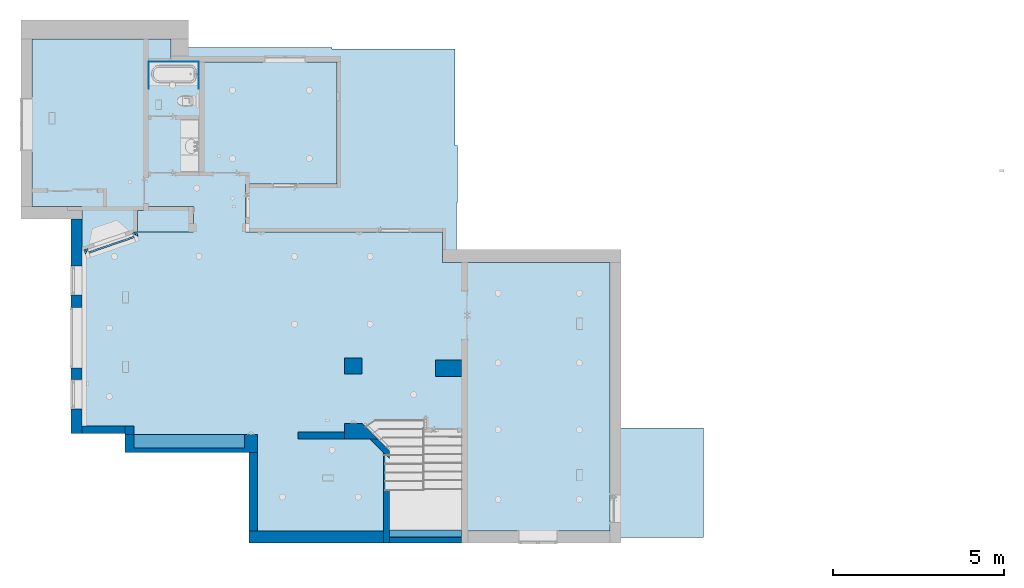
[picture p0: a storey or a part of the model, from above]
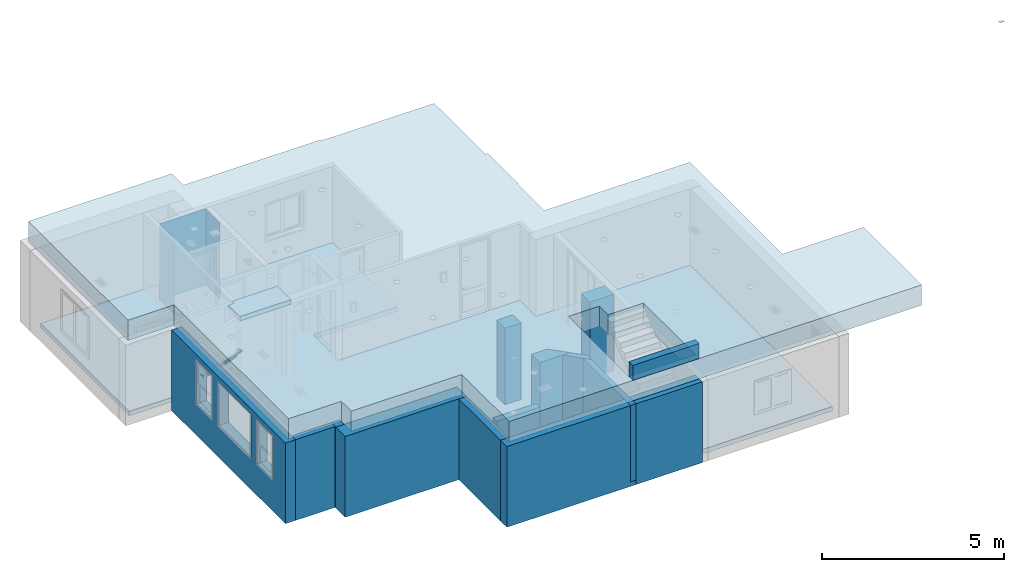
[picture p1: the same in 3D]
Properties of the parts of a building model (IFC2X3)

# File
Description: ViewDefinition [CoordinationView_V2.0, SurfaceGeometryAddOnView], Option [Elements to export: Entire project], Option [Partial Structure Display: Entire Model], Option [IFC Domain: Custom], Option [Structural Function: All Elements], Option [Convert Grid elements: On], Option [Convert IFC Annotations and ARCHICAD 2D elements: Off], Option [Convert 2D symbols of Doors and Windows: On], Option [Export geometries that Participates in Collision Detection only: On], Option [Split complex elements: Off], Option [Material Preservation: Explode where necessary], Option [IFC Model position: Survey Point and Project Origin], Option [Curtain Wall export mode: Single Element], Option [Railing export mode: Single Element], Option [Stair export mode: Single Element], Option [Properties To Export: All properties], Option [Space containment: Off], Option [Bounding Box: Off], Option [Geometry to type objects: Off], Option [Element Properties: Off], Option [Building Material Properties: Off], Option [Element Parameters: Off], Option [Component Parameters: Off], Option [IFC Base Quantities: Off], Option [Door Window Parameters: On], Option [IFC Space boundaries: Off], Option [ARCHICAD Zone Categories as IFC Space classification data: Off], Option [Element Classifications: Off]
File name: D:\PTASHKA\Canvas\Очистка\Backcountry USA\Backcountry INT.ifc
Time: 2024-10-02T13:26:50
Author: Architect
Organization: Contact Company
Written by: The EXPRESS Data Manager Version 5.02.0100.09 : 26 Sep 2013
Made in: IFC file generated by GRAPHISOFT ARCHICAD 25.0.0 INT FULL Windows version (IFC add-on version: 4013 INT FULL).
Authorization: The authorising person

# IfcSite, Site
RefLatitude: 42, 25, 2, 912200; RefLongitude: -71, -15, -30, -990400; RefElevation: 2568 in

# IfcBuildingStorey (2)
In: Building
Name | Elevation (in)
First Floor | 0
Second Floor | 127.953

# IfcSpace: Zone Names (25)
InteriorOrExteriorSpace: INTERNAL
Pset_SpaceCommon - Category: Zone Names
AC_Pset_RenovationAndPhasing - Renovation Status: Existing
Name | In | LongName
2 x 001 | First Floor | Bedroom
001 | First Floor | Storage
2 x 001 | First Floor | Bathroom
001 | First Floor | Hallway
2 x 001 | First Floor | Living room
001 | Second Floor | Kitchen
3 x 001 | Second Floor | Storage
4 x 001 | Second Floor | Hallway
2 x 001 | Second Floor | Living room
001 | Second Floor | Office
2 x 001 | Second Floor | Toilet room
001 | Second Floor | Dining room
001 | Second Floor | Bedroom
001 | Second Floor | Laundry room
001 | Second Floor | Bathroom

# IfcBeam: Plaster Cornice/Coving 125 x 205, BMR - 003
In: First Floor
Material: Generic - Structural
AC_Pset_RenovationAndPhasing - Renovation Status: New
Pset_BeamCommon - Reference: Plaster Cornice/Coving 125 x 205

# IfcBeam: Plaster Cornice/Coving 127 x 203 (2)
In: First Floor
Material: Generic - Structural
AC_Pset_RenovationAndPhasing - Renovation Status: New
Pset_BeamCommon - Reference: Plaster Cornice/Coving 127 x 203

# IfcBeam: Plaster Cornice/Coving 150 x 205 (6)
In: Second Floor
Material: Generic - Structural
AC_Pset_RenovationAndPhasing - Renovation Status: New
Pset_BeamCommon - Reference: Plaster Cornice/Coving 150 x 205

# IfcBeam: Plaster Cornice/Coving 65 x 65, BMR - 041
In: Second Floor
Material: Generic - Structural
AC_Pset_RenovationAndPhasing - Renovation Status: New
Pset_BeamCommon - Reference: Plaster Cornice/Coving 65 x 65

# IfcBeam: Tile - Wall 15 x 1120 (6)
In: Second Floor
Material: Tile - Wall
AC_Pset_RenovationAndPhasing - Renovation Status: New
Pset_BeamCommon - Reference: Tile - Wall 15 x 1120

# IfcBeam: Tile - Wall 15 x 205 (2)
In: Second Floor
Material: Tile - Wall
AC_Pset_RenovationAndPhasing - Renovation Status: New
Pset_BeamCommon - Reference: Tile - Wall 15 x 205
Name
BMR - 112
BMR - 113

# IfcBeam: Tile - Wall 15 x 2465 (4)
In: Second Floor
Material: Tile - Wall
AC_Pset_RenovationAndPhasing - Renovation Status: New
Pset_BeamCommon - Reference: Tile - Wall 15 x 2465

# IfcBeam: Tile - Wall 15 x 585 (3)
In: Second Floor
Material: Tile - Wall
AC_Pset_RenovationAndPhasing - Renovation Status: New
Pset_BeamCommon - Reference: Tile - Wall 15 x 585
Name
BMR - 113
BMR - 115
BMR - 114

# IfcBeam: Tile - Wall 5 x 125 (2)
In: Second Floor
Material: Tile - Wall
AC_Pset_RenovationAndPhasing - Renovation Status: New
Pset_BeamCommon - Reference: Tile - Wall 5 x 125

# IfcBeam: Tile - Wall 5 x 2555 (3)
In: First Floor
Material: Tile - Wall
AC_Pset_RenovationAndPhasing - Renovation Status: New
Pset_BeamCommon - Reference: Tile - Wall 5 x 2555
Name
BMR - 005
BMR - 007
BMR - 006

# IfcBeam: Tile - Wall 5 x 380 (6)
In: Second Floor
Material: Tile - Wall
AC_Pset_RenovationAndPhasing - Renovation Status: New
Pset_BeamCommon - Reference: Tile - Wall 5 x 380

# IfcBeam: Tile - Wall 6 x 76 (5)
In: Second Floor
Material: Tile - Wall
AC_Pset_RenovationAndPhasing - Renovation Status: New
Pset_BeamCommon - Reference: Tile - Wall 6 x 76

# IfcBeam: stairs floor 460 x 685, BMR - 060
In: Second Floor
Material: Generic - Structural
AC_Pset_RenovationAndPhasing - Renovation Status: New
Pset_BeamCommon - Reference: stairs floor 460 x 685

# IfcBuildingElementPart (104)
Name | In | Material
7 x Wood - Structural | First Floor | Wood - Structural
32 x Timber - Floor | First Floor | Timber - Floor
Wood - Trim | First Floor | Wood - Trim
3 x Steel - Structural | First Floor | Steel - Structural
20 x Wood - Structural | Second Floor | Wood - Structural
3 x Wood - Trim | Second Floor | Wood - Trim
38 x Steel - Structural | Second Floor | Steel - Structural

# IfcBuildingElementProxy: Base Cabinet Block 25 (28)
AC_Pset_RenovationAndPhasing - Renovation Status: New
Name | In
3 x FU - 030 | First Floor
3 x FU - 025 | Second Floor
6 x FU - 004 | Second Floor
10 x OBJ-16 | Second Floor
OBJ-15 | Second Floor
2 x FU - 026 | Second Floor
3 x FU - 007 | Second Floor

# IfcBuildingElementProxy: Base Cabinet Corner L 25, FU - 025
In: Second Floor
AC_Pset_RenovationAndPhasing - Renovation Status: New

# IfcBuildingElementProxy: Basin 25, FU - 012
In: Second Floor
AC_Pset_RenovationAndPhasing - Renovation Status: New

# IfcBuildingElementProxy: Bathtub 25, FU - 004
In: First Floor
AC_Pset_RenovationAndPhasing - Renovation Status: New

# IfcBuildingElementProxy: Bathtub Corner 25, FU - 024
In: Second Floor
AC_Pset_RenovationAndPhasing - Renovation Status: New

# IfcBuildingElementProxy: Ceiling Grille 25 (7)
In: First Floor
AC_Pset_RenovationAndPhasing - Renovation Status: New
Name
5 x FU - 013
2 x FU - 009

# IfcBuildingElementProxy: Fireplace-Traditional 25 (3)
AC_Pset_RenovationAndPhasing - Renovation Status: New
Name | In
FU - 003 | First Floor
2 x FU - 003 | Second Floor

# IfcBuildingElementProxy: GENERIC - PREFABRICATED (2)
In: Second Floor
Material: GENERIC - PREFABRICATED
AC_Pset_RenovationAndPhasing - Renovation Status: New

# IfcBuildingElementProxy: Generic - Exterior (4)
In: First Floor
Material: Generic - Exterior
AC_Pset_RenovationAndPhasing - Renovation Status: New

# IfcBuildingElementProxy: Generic - Structural (28)
Material: Generic - Structural
Name | In | Renovation Status
4 x MORPH-014 | First Floor | New
MO-22 | First Floor | New
2 x MO-01 | First Floor | New
3 x MO-11 | First Floor | New
MO-02 | First Floor | New
MORPH-013 | First Floor | New
MO-09 | First Floor | New
MORPH-016 | Second Floor | New
MORPH-013 | Second Floor | New
2 x MORPH-014 | Second Floor | New
MORPH-015 | Second Floor | New
MORPH-018 | Second Floor | New
MORPH-021 | Second Floor | New
2 x MO-11 | Second Floor | Existing
MO-12 | Second Floor | New
MO-06 | Second Floor | New
MORPH-017 | Second Floor | New
MO-05 | Second Floor | New
MORPH-001 | Second Floor | New
MO-14 | Second Floor | New

# IfcBuildingElementProxy: Glass (3)
In: Second Floor
Material: Glass
AC_Pset_RenovationAndPhasing - Renovation Status: New

# IfcBuildingElementProxy: Hood 25, FU - 017
In: Second Floor
AC_Pset_RenovationAndPhasing - Renovation Status: New

# IfcBuildingElementProxy: MISSING (2)
In: Second Floor
AC_Pset_RenovationAndPhasing - Renovation Status: New

# IfcBuildingElementProxy: Rect Floor Register 25 (7)
In: Second Floor
AC_Pset_RenovationAndPhasing - Renovation Status: New

# IfcBuildingElementProxy: Sidewall Grille 25 (8)
AC_Pset_RenovationAndPhasing - Renovation Status: New
Name | In
FU - 004 | First Floor
7 x FU - 004 | Second Floor

# IfcBuildingElementProxy: Smoke and Heat Detector 25 (5)
AC_Pset_RenovationAndPhasing - Renovation Status: New
Name | In
3 x FU - 028 | First Floor
2 x FU - 028 | Second Floor

# IfcBuildingElementProxy: Square Louver Face Ceiling Diffuser 25 (4)
In: Second Floor
AC_Pset_RenovationAndPhasing - Renovation Status: New

# IfcBuildingElementProxy: Standing Cabinet Block 25 (8)
In: Second Floor
AC_Pset_RenovationAndPhasing - Renovation Status: New
Name
6 x FU - 006
2 x OBJ-17

# IfcBuildingElementProxy: Tile - Wall, MORPH-008
In: Second Floor
Material: Tile - Wall
AC_Pset_RenovationAndPhasing - Renovation Status: New

# IfcBuildingElementProxy: Timber - Structural, MORPH-012
In: Second Floor
Material: Timber - Structural
AC_Pset_RenovationAndPhasing - Renovation Status: Existing

# IfcBuildingElementProxy: WC 25 (2)
In: Second Floor
AC_Pset_RenovationAndPhasing - Renovation Status: New

# IfcBuildingElementProxy: Wall Cabinet Block 25 (19)
In: Second Floor
AC_Pset_RenovationAndPhasing - Renovation Status: New
Name
6 x FU - 008
6 x FU - 005
7 x OBJ-21

# IfcBuildingElementProxy: Washer 25 (2)
In: Second Floor
AC_Pset_RenovationAndPhasing - Renovation Status: New

# IfcColumn: Generic - Structural 455 x 510, C-01
In: First Floor
Material: Generic - Structural
AC_Pset_RenovationAndPhasing - Renovation Status: New
Pset_ColumnCommon - LoadBearing: yes; Reference: Generic - Structural 455 x 510

# IfcColumn: Generic - Structural 485 x 760, C-01
In: First Floor
Material: Generic - Structural
AC_Pset_RenovationAndPhasing - Renovation Status: New
Pset_ColumnCommon - LoadBearing: yes; Reference: Generic - Structural 485 x 760

# IfcDoor: Door 25 (16)
Type - OperationType: SINGLE_SWING_LEFT; ParameterTakesPrecedence: no; Sizeable: no
Type - Door Lining Properties - LiningThickness: 0.393701 in; CasingThickness: 1.9685 in; CasingDepth: 0.748031 in
Type - Door Panel Properties - Panel 1 - PanelDepth: 1.5748 in; PanelOperation: SWINGING; PanelWidth: 1; PanelPosition: MIDDLE
OverallHeight: 96.4567 in
Pset_DoorCommon - ThermalTransmittance: 0
AC_Pset_RenovationAndPhasing - Renovation Status: New
Name | In | OverallWidth (in) | GlazingAreaFraction
D-26 | First Floor | 29.5276 | 0.803426
D-21 | First Floor | 29.5276 | 0.803426
D-19 | First Floor | 27.5591 | 0.73581
D-18 | First Floor | 27.5591 | 0.73581
D-03 | First Floor | 27.5591 | 0.73581
D-12 | Second Floor | 31.4961 | 0.870492
D-08 | Second Floor | 23.622 | 0.598928
D-06 | Second Floor | 35.4331 | 1.00297
D-10 | Second Floor | 27.5591 | 0.73581
D-11 | Second Floor | 27.5591 | 0.73581
D-15 | Second Floor | 27.5591 | 0.73581
D-16 | Second Floor | 29.5276 | 0.803426
D-37 | Second Floor | 27.9528 | 0.749378
D-38 | Second Floor | 27.5591 | 0.73581
D-05 | Second Floor | 35.4331 | 1.00297
D-17 | Second Floor | 35.4331 | 1.4552

# IfcDoor: Door 25, D-04
In: First Floor
Type - OperationType: SINGLE_SWING_RIGHT; ParameterTakesPrecedence: no; Sizeable: no
Type - Door Lining Properties - LiningDepth: 4.64567 in; LiningThickness: 0.590551 in; LiningOffset: 0.0787402 in; CasingThickness: 2.75591 in; CasingDepth: 0.748031 in
Type - Door Panel Properties - Panel 1 - PanelDepth: 1.5748 in; PanelOperation: SWINGING; PanelWidth: 1; PanelPosition: MIDDLE
OverallHeight: 78.7402 in; OverallWidth: 31.4961 in
Pset_DoorCommon - ThermalTransmittance: 0; GlazingAreaFraction: 0.579573
AC_Pset_RenovationAndPhasing - Renovation Status: New

# IfcDoor: Door 25 (7)
Type - OperationType: SINGLE_SWING_RIGHT; ParameterTakesPrecedence: no; Sizeable: no
Type - Door Lining Properties - LiningThickness: 0.393701 in; CasingThickness: 1.9685 in; CasingDepth: 0.748031 in
Type - Door Panel Properties - Panel 1 - PanelDepth: 1.5748 in; PanelOperation: SWINGING; PanelWidth: 1; PanelPosition: MIDDLE
Pset_DoorCommon - ThermalTransmittance: 0
AC_Pset_RenovationAndPhasing - Renovation Status: New
Name | In | OverallHeight (in) | OverallWidth (in) | GlazingAreaFraction
D-31 | First Floor | 82.6772 | 29.5276 | 0.603926
D-01 | First Floor | 96.4567 | 35.4331 | 1.00297
D-02 | First Floor | 96.4567 | 27.5511 | 0.735538
D-07 | Second Floor | 96.4567 | 35.4331 | 1.00297
D-09 | Second Floor | 96.4567 | 35.4331 | 1.00297
D-14 | Second Floor | 96.4567 | 29.5157 | 0.803022
D-13 | Second Floor | 96.4567 | 29.5276 | 0.803426

# IfcDoor: Double Door 25 (2)
Type - OperationType: DOUBLE_DOOR_SINGLE_SWING; ParameterTakesPrecedence: no; Sizeable: no
Type - Door Lining Properties - LiningThickness: 0.393701 in; CasingThickness: 1.9685 in; CasingDepth: 0.748031 in
Type - Door Panel Properties - Panel 1 - PanelDepth: 1.5748 in; PanelOperation: SWINGING; PanelWidth: 0.5; PanelPosition: RIGHT
Type - Door Panel Properties - Panel 2 - PanelDepth: 1.5748 in; PanelOperation: SWINGING; PanelWidth: 0.5; PanelPosition: LEFT
OverallHeight: 96.4567 in
Pset_DoorCommon - ThermalTransmittance: 0
AC_Pset_RenovationAndPhasing - Renovation Status: New
Name | In | OverallWidth (in) | GlazingAreaFraction
D-30 | First Floor | 55.1181 | 2.0972
D-39 | Second Floor | 55.9055 | 2.14

# IfcDoor: Double Door with 2 Sidelights 25, D-43
In: Second Floor
Type - OperationType: USERDEFINED; ParameterTakesPrecedence: no; Sizeable: no
OverallHeight: 94.4882 in; OverallWidth: 112.205 in
Pset_DoorCommon - ThermalTransmittance: 0; GlazingAreaFraction: 5.2182
AC_Pset_RenovationAndPhasing - Renovation Status: New

# IfcDoor: Sliding Door 25 (2)
Type - OperationType: USERDEFINED; ParameterTakesPrecedence: no; Sizeable: no
Pset_DoorCommon - ThermalTransmittance: 0
AC_Pset_RenovationAndPhasing - Renovation Status: New
Name | In | OverallHeight (in) | OverallWidth (in)
D-29 | First Floor | 94.4882 | 57.0866
D-34 | Second Floor | 92.3228 | 70.0787 | Pset_DoorCommon - GlazingAreaFraction: 2.849

# IfcFlowTerminal: Ceiling Ventillator 25 (3)
In: Second Floor
AC_Pset_RenovationAndPhasing - Renovation Status: New

# IfcFlowTerminal: Countertop 25, OBJ-97
In: Second Floor
AC_Pset_RenovationAndPhasing - Renovation Status: New

# IfcFlowTerminal: Dishwasher Built-in 25, OBJ-96
In: Second Floor
AC_Pset_RenovationAndPhasing - Renovation Status: New

# IfcFlowTerminal: Fluorescent Lamp 25 (2)
In: Second Floor
AC_Pset_RenovationAndPhasing - Renovation Status: New

# IfcFlowTerminal: Oven Built-in 25 (2)
In: Second Floor
AC_Pset_RenovationAndPhasing - Renovation Status: New
Name
OBJ-19
OBJ-20

# IfcFlowTerminal: Pendant Lamp 25 (7)
In: Second Floor
AC_Pset_RenovationAndPhasing - Renovation Status: New

# IfcFlowTerminal: Recessed Spot 25 (52)
AC_Pset_RenovationAndPhasing - Renovation Status: New
Name | In
26 x L-03 | First Floor
26 x L-03 | Second Floor

# IfcFlowTerminal: Rect Louver Face Ceiling Diffuser 25, FU - 027
In: First Floor
AC_Pset_RenovationAndPhasing - Renovation Status: New

# IfcFlowTerminal: Refrigerator Side by Side 25, OBJ-18
In: Second Floor
AC_Pset_RenovationAndPhasing - Renovation Status: New

# IfcFlowTerminal: Wall Lamp 25 (6)
AC_Pset_RenovationAndPhasing - Renovation Status: New
Name | In
4 x L-17 | First Floor
2 x L-17 | Second Floor

# IfcFlowTerminal: Wall Spotlight 25 (4)
AC_Pset_RenovationAndPhasing - Renovation Status: New
Name | In
L-11 | First Floor
3 x L-11 | Second Floor

# IfcFurnishingElement: Range Gas 25, FU - 016
In: Second Floor
AC_Pset_RenovationAndPhasing - Renovation Status: New

# IfcFurnishingElement: WC 25, FU - 028
In: First Floor
AC_Pset_RenovationAndPhasing - Renovation Status: New

# IfcRailing: Railing Type (8)
Pset_PrecastConcreteElementGeneral - SerialNumber: Undefined; sets with these values: 2
AC_Pset_RenovationAndPhasing - Renovation Status: New
Name | In
RAILING - 001 | First Floor
RAILING - 003 | First Floor
RA-03 | Second Floor
5 x RAILING - 001 | Second Floor

# IfcSlab: Generic - Structural 100, SLA - 019
In: Second Floor
Type - PredefinedType: FLOOR
Material: Generic - Structural
AC_Pset_RenovationAndPhasing - Renovation Status: New

# IfcSlab: Generic - Structural 150 (13)
In: Second Floor
Type - PredefinedType: FLOOR
Material: Generic - Structural
AC_Pset_RenovationAndPhasing - Renovation Status: New
Name
SLA - 010
SLA - 014
SLA - 002
SLA - 004
SLA - 005
SLA - 006
SLA - 007
SLA - 008
SLA - 012
2 x SLA - 016
SLA - 017
SLA - 018

# IfcSlab: Generic - Structural 152, SLA - 003
In: First Floor
Type - PredefinedType: FLOOR
Material: Generic - Structural
AC_Pset_RenovationAndPhasing - Renovation Status: New

# IfcSlab: Generic - Structural 355 (2)
In: Second Floor
Type - PredefinedType: FLOOR
Material: Generic - Structural
AC_Pset_RenovationAndPhasing - Renovation Status: New
Name
SLA - 003
SLA - 013

# IfcSlab: Generic - Structural 470 (2)
In: Second Floor
Type - PredefinedType: FLOOR
Material: Generic - Structural
AC_Pset_RenovationAndPhasing - Renovation Status: New
Name
SLA - 015
SLA - 011

# IfcSlab: Generic - Structural 495, SLA - 009
In: Second Floor
Type - PredefinedType: FLOOR
Material: Generic - Structural
AC_Pset_RenovationAndPhasing - Renovation Status: New

# IfcSlab: Generic - Structural 685, SLA - 002
In: First Floor
Type - PredefinedType: FLOOR
Material: Generic - Structural
AC_Pset_RenovationAndPhasing - Renovation Status: New

# IfcSlab: Generic - Structural 825, SLA - 010
In: Second Floor
Type - PredefinedType: FLOOR
Material: Generic - Structural
AC_Pset_RenovationAndPhasing - Renovation Status: New

# IfcSlab: Generic Floor/Ceiling Slab 150mm 150, S-01
In: First Floor
Type - PredefinedType: FLOOR
Material: Generic - Structural
AC_Pset_RenovationAndPhasing - Renovation Status: New
Pset_SlabCommon - LoadBearing: yes; IsExternal: no

# IfcStair, STAIR-30
In: First Floor
Pset_StairCommon - NumberOfRiser: 16; NumberOfTreads: 16; RiserHeight: 7.57874 in; RequiredHeadroom: 80 in; IsExternal: no
AC_Pset_RenovationAndPhasing - Renovation Status: New

# IfcWall: Generic - Structural 115 (34)
Material: Generic - Structural
AC_Pset_RenovationAndPhasing - Renovation Status: New
Name | In
SW - 018 | First Floor
W-16 | First Floor | Pset_WallCommon - LoadBearing: yes; IsExternal: yes
W-17 | First Floor | Pset_WallCommon - LoadBearing: yes; IsExternal: yes
SW - 017 | First Floor
2 x SW - 051 | First Floor
2 x SW - 057 | First Floor
SW - 066 | First Floor
SW - 146 | First Floor
SW - 054 | First Floor
SW - 015 | First Floor
SW - 058 | First Floor
SW - 016 | First Floor
SW - 059 | First Floor
SW - 131 | Second Floor
W-12 | Second Floor | Pset_WallCommon - LoadBearing: yes; IsExternal: yes
W-03 | Second Floor | Pset_WallCommon - LoadBearing: yes; IsExternal: yes
SW - 130 | Second Floor
SW - 100 | Second Floor
2 x SW - 110 | Second Floor
SW - 119 | Second Floor
SW - 117 | Second Floor
SW - 107 | Second Floor
SW - 135 | Second Floor
SW - 106 | Second Floor
SW - 101 | Second Floor
SW - 132 | Second Floor
SW - 084 | Second Floor
SW - 082 | Second Floor
SW - 078 | Second Floor
SW - 075 | Second Floor
SW - 015 | Second Floor

# IfcWall: Generic - Structural 140 (6)
Material: Generic - Structural
AC_Pset_RenovationAndPhasing - Renovation Status: New
Name | In
SW - 052 | First Floor
SW - 077 | Second Floor
SW - 106 | Second Floor
SW - 104 | Second Floor
SW - 126 | Second Floor
SW - 079 | Second Floor

# IfcWall: Generic - Structural 150, SW - 067
In: First Floor
Material: Generic - Structural
AC_Pset_RenovationAndPhasing - Renovation Status: New

# IfcWall: Generic - Structural 165 (7)
Material: Generic - Structural
AC_Pset_RenovationAndPhasing - Renovation Status: New
Name | In
SW - 036 | First Floor
SW - 035 | First Floor
SW - 055 | First Floor
2 x SW - 123 | Second Floor
SW - 122 | Second Floor
SW - 121 | Second Floor

# IfcWall: Generic - Structural 170, SW - 080
In: Second Floor
Material: Generic - Structural
AC_Pset_RenovationAndPhasing - Renovation Status: New

# IfcWall: Generic - Structural 190 (3)
Material: Generic - Structural
AC_Pset_RenovationAndPhasing - Renovation Status: New
Name | In
SW - 044 | First Floor
SW - 130 | Second Floor
SW - 102 | Second Floor

# IfcWall: Generic - Structural 200 (2)
In: Second Floor
Material: Generic - Structural
AC_Pset_RenovationAndPhasing - Renovation Status: New
Name
SW - 116
SW - 081

# IfcWall: Generic - Structural 205 (5)
Material: Generic - Structural
AC_Pset_RenovationAndPhasing - Renovation Status: New
Name | In
SW - 073 | First Floor
2 x SW - 128 | Second Floor
SW - 124 | Second Floor
SW - 018 | Second Floor

# IfcWall: Generic - Structural 215 (6)
Material: Generic - Structural
AC_Pset_RenovationAndPhasing - Renovation Status: New
Name | In
SW - 020 | First Floor
SW - 024 | First Floor
SW - 129 | Second Floor
SW - 111 | Second Floor
SW - 092 | Second Floor
SW - 090 | Second Floor

# IfcWall: Generic - Structural 230, SW - 086
In: Second Floor
Material: Generic - Structural
AC_Pset_RenovationAndPhasing - Renovation Status: New

# IfcWall: Generic - Structural 240, SW - 108
In: Second Floor
Material: Generic - Structural
AC_Pset_RenovationAndPhasing - Renovation Status: New

# IfcWall: Generic - Structural 250, SW - 025
In: First Floor
Material: Generic - Structural
AC_Pset_RenovationAndPhasing - Renovation Status: New

# IfcWall: Generic - Structural 255 (2)
Material: Generic - Structural
AC_Pset_RenovationAndPhasing - Renovation Status: New
Name | In
SW - 016 | First Floor
SW - 099 | Second Floor

# IfcWall: Generic - Structural 265, SW - 021
In: First Floor
Material: Generic - Structural
AC_Pset_RenovationAndPhasing - Renovation Status: New

# IfcWall: Generic - Structural 280, SW - 089
In: Second Floor
Material: Generic - Structural
AC_Pset_RenovationAndPhasing - Renovation Status: New

# IfcWall: Generic - Structural 320 (2)
In: First Floor
Material: Generic - Structural
AC_Pset_RenovationAndPhasing - Renovation Status: New
Name
SW - 019
SW - 064

# IfcWall: Generic - Structural 322, SW - 020
In: Second Floor
Material: Generic - Structural
AC_Pset_RenovationAndPhasing - Renovation Status: New

# IfcWall: Generic - Structural 325, SW - 048
In: First Floor
Material: Generic - Structural
AC_Pset_RenovationAndPhasing - Renovation Status: New

# IfcWall: Generic - Structural 350, SW - 026
In: First Floor
Material: Generic - Structural
AC_Pset_RenovationAndPhasing - Renovation Status: New

# IfcWall: Generic - Structural 355, SW - 063
In: First Floor
Material: Generic - Structural
AC_Pset_RenovationAndPhasing - Renovation Status: New

# IfcWall: Generic - Structural 370, SW - 051
In: First Floor
Material: Generic - Structural
AC_Pset_RenovationAndPhasing - Renovation Status: New

# IfcWall: Generic - Structural 380, SW - 014
In: First Floor
Material: Generic - Structural
AC_Pset_RenovationAndPhasing - Renovation Status: New

# IfcWall: Generic - Structural 430, SW - 020
In: Second Floor
Material: Generic - Structural
AC_Pset_RenovationAndPhasing - Renovation Status: New

# IfcWall: Generic - Structural 455, SW - 068
In: First Floor
Material: Generic - Structural
AC_Pset_RenovationAndPhasing - Renovation Status: New

# IfcWall: Generic - Structural 520 (2)
In: First Floor
Material: Generic - Structural
AC_Pset_RenovationAndPhasing - Renovation Status: New
Name
SW - 022
SW - 053

# IfcWall: Generic - Structural 560, SW - 053
In: First Floor
Material: Generic - Structural
AC_Pset_RenovationAndPhasing - Renovation Status: New

# IfcWall: Generic - Structural 90, SW - 014
In: Second Floor
Material: Generic - Structural
AC_Pset_RenovationAndPhasing - Renovation Status: New

# IfcWall: Generic - Structural Polygonal, SW - 127
In: Second Floor
Material: Generic - Structural
AC_Pset_RenovationAndPhasing - Renovation Status: New

# IfcWall: Generic Wall 4.5" 114 (5)
Material: Generic - Structural
AC_Pset_RenovationAndPhasing - Renovation Status: New
Name | In
SW - 039 | First Floor
W-03 | Second Floor | Pset_WallCommon - LoadBearing: yes; IsExternal: yes
SW - 115 | Second Floor
SW - 138 | Second Floor
SW - 137 | Second Floor

# IfcWall: Generic Wall 6.5" 165 (26)
Material: Generic - Structural
AC_Pset_RenovationAndPhasing - Renovation Status: New
Name | In
SW - 056 | First Floor
SW - 037 | First Floor
3 x SW - 102 | Second Floor
SW - 129 | Second Floor
2 x SW - 093 | Second Floor
SW - 087 | Second Floor
SW - 116 | Second Floor
2 x SW - 120 | Second Floor
SW - 080 | Second Floor
SW - 118 | Second Floor
SW - 112 | Second Floor
SW - 134 | Second Floor
SW - 109 | Second Floor
SW - 099 | Second Floor
SW - 105 | Second Floor
SW - 098 | Second Floor
SW - 145 | Second Floor
SW - 136 | Second Floor
2 x SW - 088 | Second Floor
SW - 076 | Second Floor
SW - 086 | Second Floor

# IfcWindow: Double Sash Window 25 (2)
In: First Floor
Type - OperationType: DOUBLE_PANEL_VERTICAL; ParameterTakesPrecedence: no; Sizeable: no
Type - Window Lining Properties - LiningDepth: 1.9685 in; LiningThickness: 1.5748 in; MullionThickness: 1.5748 in; FirstMullionOffset: 0.5
Type - Window Panel Properties - Panel 1 - OperationType: SIDEHUNGLEFTHAND; PanelPosition: RIGHT; FrameDepth: 1.9685 in; FrameThickness: 1.9685 in
Type - Window Panel Properties - Panel 2 - OperationType: SIDEHUNGRIGHTHAND; PanelPosition: LEFT; FrameDepth: 1.9685 in; FrameThickness: 1.9685 in
Pset_WindowCommon - ThermalTransmittance: 0; IsExternal: yes
AC_Pset_RenovationAndPhasing - Renovation Status: New
Name | OverallHeight (in) | OverallWidth (in) | GlazingAreaFraction
W-05 | 55.1181 | 59.0551 | 1.6129
W-06 | 46.8504 | 46.063 | 0.9964

# IfcWindow: Double Sash Window 25, W-04
In: First Floor
Type - OperationType: DOUBLE_PANEL_VERTICAL; ParameterTakesPrecedence: no; Sizeable: no
Type - Window Lining Properties - LiningDepth: 1.9685 in; LiningThickness: 1.5748 in; MullionThickness: 1.5748 in; FirstMullionOffset: 0.5
Type - Window Panel Properties - Panel 1 - OperationType: SIDEHUNGRIGHTHAND; PanelPosition: LEFT; FrameDepth: 1.9685 in; FrameThickness: 1.9685 in
Type - Window Panel Properties - Panel 2 - OperationType: SIDEHUNGLEFTHAND; PanelPosition: RIGHT; FrameDepth: 1.9685 in; FrameThickness: 1.9685 in
OverallHeight: 43.1102 in; OverallWidth: 44.0945 in
Pset_WindowCommon - ThermalTransmittance: 0; GlazingAreaFraction: 0.85885; IsExternal: yes
AC_Pset_RenovationAndPhasing - Renovation Status: New

# IfcWindow: Double Window 25, W-23
In: Second Floor
Type - OperationType: DOUBLE_PANEL_VERTICAL; ParameterTakesPrecedence: no; Sizeable: no
Type - Window Lining Properties - LiningDepth: 1.9685 in; LiningThickness: 2.55906 in; MullionThickness: 2.55906 in; FirstMullionOffset: 0.5
Type - Window Panel Properties - Panel 1 - OperationType: SIDEHUNGLEFTHAND; PanelPosition: RIGHT; FrameDepth: 1.9685 in; FrameThickness: 1.77165 in
Type - Window Panel Properties - Panel 2 - OperationType: SIDEHUNGRIGHTHAND; PanelPosition: LEFT; FrameDepth: 1.9685 in; FrameThickness: 1.77165 in
OverallHeight: 69.685 in; OverallWidth: 79.9213 in
Pset_WindowCommon - ThermalTransmittance: 0; GlazingAreaFraction: 2.808; IsExternal: yes
AC_Pset_RenovationAndPhasing - Renovation Status: New

# IfcWindow: Double Window 25, W-18
In: Second Floor
Type - OperationType: DOUBLE_PANEL_VERTICAL; ParameterTakesPrecedence: no; Sizeable: no
Type - Window Lining Properties - LiningDepth: 1.9685 in; LiningThickness: 3.54331 in; MullionThickness: 3.54331 in; FirstMullionOffset: 0.5
Type - Window Panel Properties - Panel 1 - OperationType: SIDEHUNGLEFTHAND; PanelPosition: RIGHT; FrameDepth: 1.9685 in; FrameThickness: 1.5748 in
Type - Window Panel Properties - Panel 2 - OperationType: SIDEHUNGRIGHTHAND; PanelPosition: LEFT; FrameDepth: 1.9685 in; FrameThickness: 1.5748 in
OverallHeight: 59.8463 in; OverallWidth: 69.2913 in
Pset_WindowCommon - ThermalTransmittance: 0; GlazingAreaFraction: 1.70312; IsExternal: yes
AC_Pset_RenovationAndPhasing - Renovation Status: New

# IfcWindow: Double-Hung Window 25 (2)
In: Second Floor
Type - OperationType: DOUBLE_PANEL_HORIZONTAL; ParameterTakesPrecedence: no; Sizeable: no
Type - Window Lining Properties - LiningDepth: 3.93701 in; LiningThickness: 1.49606 in; TransomThickness: 2.24409 in; FirstTransomOffset: 0.5
Type - Window Panel Properties - Panel 1 - OperationType: SLIDINGVERTICAL; PanelPosition: TOP; FrameDepth: 1.9685 in; FrameThickness: 2.24409 in
Type - Window Panel Properties - Panel 2 - OperationType: SLIDINGVERTICAL; PanelPosition: BOTTOM; FrameDepth: 1.9685 in; FrameThickness: 2.24409 in
OverallHeight: 69.2913 in; OverallWidth: 34.4488 in
Pset_WindowCommon - ThermalTransmittance: 0; GlazingAreaFraction: 1.03641; IsExternal: yes
AC_Pset_RenovationAndPhasing - Renovation Status: New
Name
W-29
W-30

# IfcWindow: Double-Hung Window 25 (6)
Type - OperationType: DOUBLE_PANEL_HORIZONTAL; ParameterTakesPrecedence: no; Sizeable: no
Type - Window Lining Properties - LiningDepth: 3.93701 in; LiningThickness: 1.5748 in; TransomThickness: 1.9685 in; FirstTransomOffset: 0.5
Type - Window Panel Properties - Panel 1 - OperationType: SLIDINGVERTICAL; PanelPosition: TOP; FrameDepth: 1.9685 in; FrameThickness: 1.9685 in
Type - Window Panel Properties - Panel 2 - OperationType: SLIDINGVERTICAL; PanelPosition: BOTTOM; FrameDepth: 1.9685 in; FrameThickness: 1.9685 in
Pset_WindowCommon - ThermalTransmittance: 0; IsExternal: yes
AC_Pset_RenovationAndPhasing - Renovation Status: New
Name | In | OverallHeight (in) | OverallWidth (in) | GlazingAreaFraction
W-01 | First Floor | 57.0866 | 33.4646 | 0.8174
W-02 | First Floor | 57.0866 | 33.4646 | 0.8174
W-12 | Second Floor | 67.5197 | 34.0551 | 1.01723
W-13 | Second Floor | 67.5197 | 34.0551 | 1.01723
W-07 | Second Floor | 69.685 | 29.9213 | 0.8932
W-11 | Second Floor | 45.6693 | 22.0472 | 0.3534

# IfcWindow: Double-Hung Window 25, W-35
In: Second Floor
Type - OperationType: DOUBLE_PANEL_HORIZONTAL; ParameterTakesPrecedence: no; Sizeable: no
Type - Window Lining Properties - LiningDepth: 3.93701 in; LiningThickness: 1.5748 in; TransomThickness: 2.16535 in; FirstTransomOffset: 0.5
Type - Window Panel Properties - Panel 1 - OperationType: SLIDINGVERTICAL; PanelPosition: TOP; FrameDepth: 1.9685 in; FrameThickness: 2.16535 in
Type - Window Panel Properties - Panel 2 - OperationType: SLIDINGVERTICAL; PanelPosition: BOTTOM; FrameDepth: 1.9685 in; FrameThickness: 2.16535 in
OverallHeight: 45.4724 in; OverallWidth: 29.3307 in
Pset_WindowCommon - ThermalTransmittance: 0; GlazingAreaFraction: 0.50505; IsExternal: yes
AC_Pset_RenovationAndPhasing - Renovation Status: New

# IfcWindow: Window 25, W-28
In: Second Floor
Type - OperationType: SINGLE_PANEL; ParameterTakesPrecedence: no; Sizeable: no
Type - Window Lining Properties - LiningDepth: 1.9685 in; LiningThickness: 1.49606 in
Type - Window Panel Properties - Panel 1 - OperationType: SIDEHUNGLEFTHAND; PanelPosition: MIDDLE; FrameDepth: 1.9685 in; FrameThickness: 1.25984 in
OverallHeight: 45.4724 in; OverallWidth: 25.1969 in
Pset_WindowCommon - ThermalTransmittance: 0; GlazingAreaFraction: 0.58575; IsExternal: yes
AC_Pset_RenovationAndPhasing - Renovation Status: New

# IfcWindow: Window 25 (4)
In: Second Floor
Type - OperationType: SINGLE_PANEL; ParameterTakesPrecedence: no; Sizeable: no
Type - Window Lining Properties - LiningDepth: 1.9685 in; LiningThickness: 1.49606 in
Type - Window Panel Properties - Panel 1 - OperationType: SIDEHUNGRIGHTHAND; PanelPosition: MIDDLE; FrameDepth: 1.9685 in; FrameThickness: 1.25984 in
OverallHeight: 45.4724 in
Pset_WindowCommon - ThermalTransmittance: 0; IsExternal: yes
AC_Pset_RenovationAndPhasing - Renovation Status: New
Name | OverallWidth (in) | GlazingAreaFraction
W-32 | 25.5906 | 0.5964
W-33 | 25.5906 | 0.5964
W-34 | 25.5906 | 0.5964
W-26 | 25.1969 | 0.58575

# IfcWindow: Window 25, W-31
In: Second Floor
Type - OperationType: SINGLE_PANEL; ParameterTakesPrecedence: no; Sizeable: no
Type - Window Lining Properties - LiningDepth: 1.9685 in; LiningThickness: 1.5748 in
Type - Window Panel Properties - Panel 1 - OperationType: SIDEHUNGRIGHTHAND; PanelPosition: MIDDLE; FrameDepth: 1.9685 in; FrameThickness: 1.25984 in
OverallHeight: 69.2913 in; OverallWidth: 59.8425 in
Pset_WindowCommon - ThermalTransmittance: 0; GlazingAreaFraction: 2.37572; IsExternal: yes
AC_Pset_RenovationAndPhasing - Renovation Status: New

# IfcWindow: Window 25, W-03
In: First Floor
Type - OperationType: SINGLE_PANEL; ParameterTakesPrecedence: no; Sizeable: no
Type - Window Lining Properties - LiningDepth: 1.9685 in; LiningThickness: 1.5748 in
Type - Window Panel Properties - Panel 1 - OperationType: SIDEHUNGRIGHTHAND; PanelPosition: MIDDLE; FrameDepth: 1.9685 in; FrameThickness: 1.9685 in
OverallHeight: 57.0866 in; OverallWidth: 70.0787 in
Pset_WindowCommon - ThermalTransmittance: 0; GlazingAreaFraction: 2.178; IsExternal: yes
AC_Pset_RenovationAndPhasing - Renovation Status: New

# IfcWindow: Window 25, W-40
In: Second Floor
Type - OperationType: SINGLE_PANEL; ParameterTakesPrecedence: no; Sizeable: no
Type - Window Lining Properties - LiningDepth: 1.9685 in; LiningThickness: 2.48031 in
Type - Window Panel Properties - Panel 1 - OperationType: SIDEHUNGLEFTHAND; PanelPosition: MIDDLE; FrameDepth: 1.5748 in; FrameThickness: 0.23622 in
OverallHeight: 30.7087 in; OverallWidth: 29.9213 in
Pset_WindowCommon - ThermalTransmittance: 0; GlazingAreaFraction: 0.465024; IsExternal: yes
AC_Pset_RenovationAndPhasing - Renovation Status: New

# IfcWindow: Window 25, W-39
In: Second Floor
Type - OperationType: SINGLE_PANEL; ParameterTakesPrecedence: no; Sizeable: no
Type - Window Lining Properties - LiningDepth: 1.9685 in; LiningThickness: 2.48031 in
Type - Window Panel Properties - Panel 1 - OperationType: SIDEHUNGRIGHTHAND; PanelPosition: MIDDLE; FrameDepth: 1.5748 in; FrameThickness: 0.23622 in
OverallHeight: 30.7087 in; OverallWidth: 29.9213 in
Pset_WindowCommon - ThermalTransmittance: 0; GlazingAreaFraction: 0.465024; IsExternal: yes
AC_Pset_RenovationAndPhasing - Renovation Status: New

# IfcWindow: Window 25 (2)
In: Second Floor
Type - OperationType: SINGLE_PANEL; ParameterTakesPrecedence: no; Sizeable: no
Type - Window Lining Properties - LiningDepth: 2.75591 in; LiningThickness: 1.9685 in
Type - Window Panel Properties - Panel 1 - OperationType: SIDEHUNGLEFTHAND; PanelPosition: MIDDLE; FrameDepth: 1.9685 in; FrameThickness: 1.9685 in
OverallHeight: 29.9213 in; OverallWidth: 34.0551 in
Pset_WindowCommon - ThermalTransmittance: 0; GlazingAreaFraction: 0.43615; IsExternal: yes
AC_Pset_RenovationAndPhasing - Renovation Status: New
Name
W-15
W-16

# IfcWindow: Window 25, W-14
In: Second Floor
Type - OperationType: SINGLE_PANEL; ParameterTakesPrecedence: no; Sizeable: no
Type - Window Lining Properties - LiningDepth: 2.75591 in; LiningThickness: 1.9685 in
Type - Window Panel Properties - Panel 1 - OperationType: SIDEHUNGRIGHTHAND; PanelPosition: MIDDLE; FrameDepth: 1.9685 in; FrameThickness: 1.9685 in
OverallHeight: 29.9213 in; OverallWidth: 34.0551 in
Pset_WindowCommon - ThermalTransmittance: 0; GlazingAreaFraction: 0.43615; IsExternal: yes
AC_Pset_RenovationAndPhasing - Renovation Status: New

# IfcWindow: Window 25, W-08
In: Second Floor
Type - OperationType: SINGLE_PANEL; ParameterTakesPrecedence: no; Sizeable: no
Type - Window Lining Properties - LiningDepth: 6.10236 in; LiningThickness: 1.1811 in
Type - Window Panel Properties - Panel 1 - OperationType: SIDEHUNGLEFTHAND; PanelPosition: MIDDLE; FrameDepth: 1.9685 in; FrameThickness: 1.77165 in
OverallHeight: 29.9222 in; OverallWidth: 29.7244 in
Pset_WindowCommon - ThermalTransmittance: 0; GlazingAreaFraction: 0.432315; IsExternal: yes
AC_Pset_RenovationAndPhasing - Renovation Status: New

# IfcWindow: Window 25, W-10
In: Second Floor
Type - OperationType: SINGLE_PANEL; ParameterTakesPrecedence: no; Sizeable: no
Type - Window Lining Properties - LiningDepth: 6.10236 in; LiningThickness: 1.1811 in
Type - Window Panel Properties - Panel 1 - OperationType: SIDEHUNGRIGHTHAND; PanelPosition: MIDDLE; FrameDepth: 1.9685 in; FrameThickness: 1.77165 in
OverallHeight: 29.9213 in; OverallWidth: 29.7244 in
Pset_WindowCommon - ThermalTransmittance: 0; GlazingAreaFraction: 0.4323; IsExternal: yes
AC_Pset_RenovationAndPhasing - Renovation Status: New

# IfcWindow: Window 25, W-09
In: Second Floor
Type - OperationType: SINGLE_PANEL; ParameterTakesPrecedence: no; Sizeable: no
Type - Window Lining Properties - LiningDepth: 6.10236 in; LiningThickness: 1.1811 in
Type - Window Panel Properties - Panel 1 - OperationType: SIDEHUNGRIGHTHAND; PanelPosition: MIDDLE; FrameDepth: 1.9685 in; FrameThickness: 1.9685 in
OverallHeight: 29.9213 in; OverallWidth: 29.7244 in
Pset_WindowCommon - ThermalTransmittance: 0; GlazingAreaFraction: 0.41925; IsExternal: yes
AC_Pset_RenovationAndPhasing - Renovation Status: New
